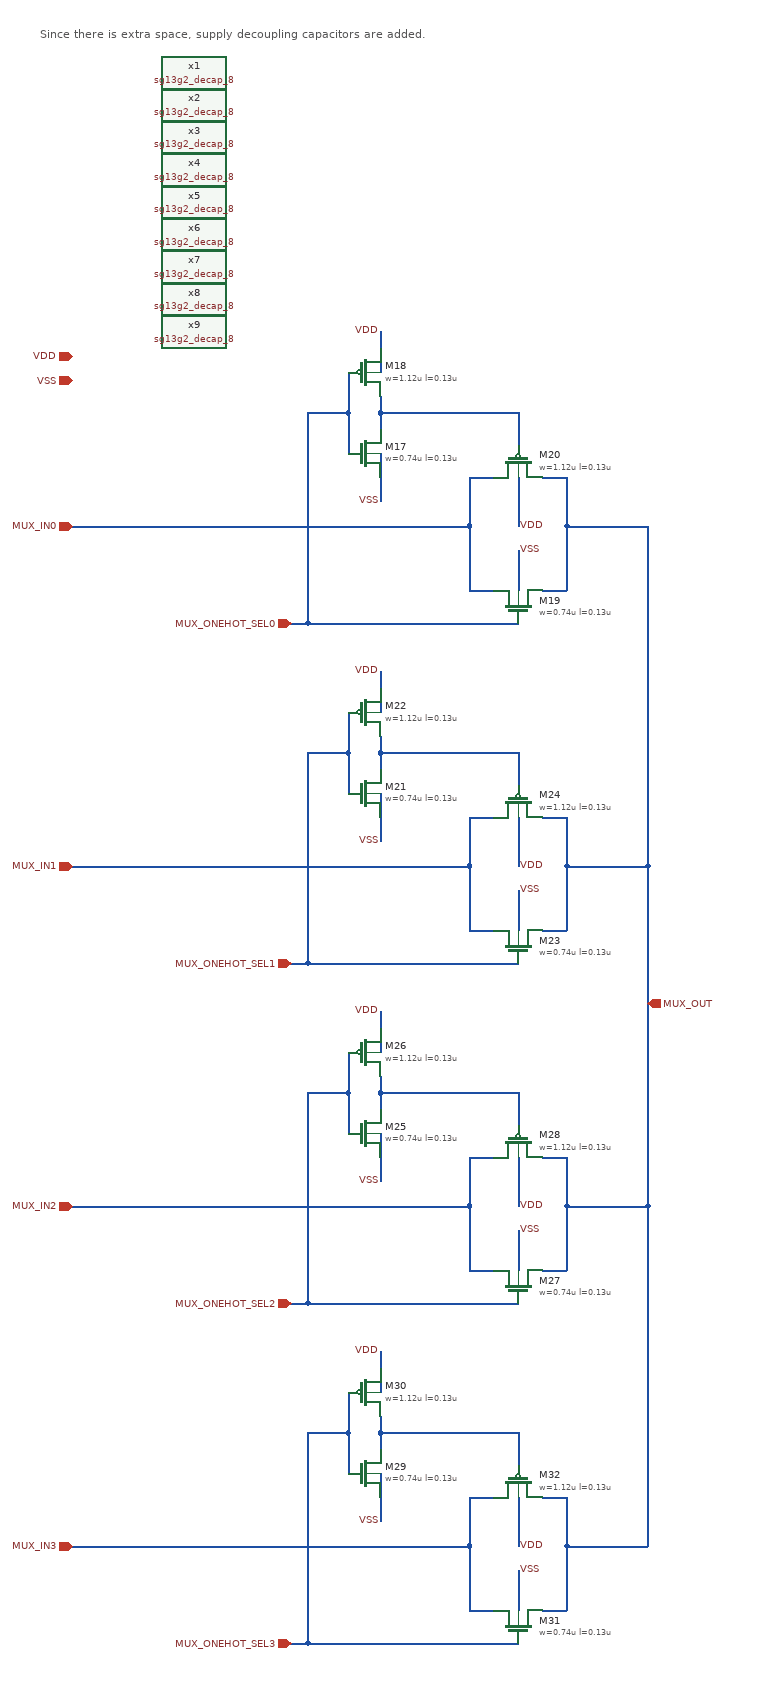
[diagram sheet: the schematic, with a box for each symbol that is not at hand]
v {xschem version=3.4.8RC file_version=1.3}
G {}
K {dash=3}
V {}
S {}
F {}
E {}
T {Since there is extra space, supply decoupling capacitors are added.} -370 -510 0 0 0.4 0.4 {}
N 50 -30 50 -10 {lab=#net1}
N 50 -30 220 -30 {lab=#net1}
N 50 -50 50 -30 {lab=#net1}
N 10 -30 10 20 {lab=MUX_ONEHOT_SEL0}
N 280 110 280 190 {lab=MUX_OUT}
N 220 50 220 110 {lab=VDD}
N 220 140 220 190 {lab=VSS}
N 280 50 280 110 {lab=MUX_OUT}
N 160 50 160 110 {lab=MUX_IN0}
N 160 50 190 50 {lab=MUX_IN0}
N 160 110 160 190 {lab=MUX_IN0}
N 160 190 190 190 {lab=MUX_IN0}
N 250 50 280 50 {lab=MUX_OUT}
N 250 190 280 190 {lab=MUX_OUT}
N 380 530 380 950 {lab=MUX_OUT}
N 220 -30 220 10 {lab=#net1}
N 10 -80 10 -30 {lab=MUX_ONEHOT_SEL0}
N -40 230 220 230 {lab=MUX_ONEHOT_SEL0}
N -40 -30 -40 230 {lab=MUX_ONEHOT_SEL0}
N -40 -30 10 -30 {lab=MUX_ONEHOT_SEL0}
N 50 -130 50 -80 {lab=VDD}
N -60 230 -40 230 {lab=MUX_ONEHOT_SEL0}
N 280 110 380 110 {lab=MUX_OUT}
N 50 20 50 80 {lab=VSS}
N 50 390 50 410 {lab=#net2}
N 50 390 220 390 {lab=#net2}
N 50 370 50 390 {lab=#net2}
N 10 390 10 440 {lab=MUX_ONEHOT_SEL1}
N 280 530 280 610 {lab=MUX_OUT}
N 220 470 220 530 {lab=VDD}
N 220 560 220 610 {lab=VSS}
N 280 470 280 530 {lab=MUX_OUT}
N 160 470 160 530 {lab=MUX_IN1}
N 160 470 190 470 {lab=MUX_IN1}
N 160 530 160 610 {lab=MUX_IN1}
N 160 610 190 610 {lab=MUX_IN1}
N 250 470 280 470 {lab=MUX_OUT}
N 250 610 280 610 {lab=MUX_OUT}
N 220 390 220 430 {lab=#net2}
N 10 340 10 390 {lab=MUX_ONEHOT_SEL1}
N -40 650 220 650 {lab=MUX_ONEHOT_SEL1}
N -40 390 -40 650 {lab=MUX_ONEHOT_SEL1}
N -40 390 10 390 {lab=MUX_ONEHOT_SEL1}
N 50 290 50 340 {lab=VDD}
N -60 650 -40 650 {lab=MUX_ONEHOT_SEL1}
N 280 530 380 530 {lab=MUX_OUT}
N 50 440 50 500 {lab=VSS}
N 380 110 380 530 {lab=MUX_OUT}
N 50 810 50 830 {lab=#net3}
N 50 810 220 810 {lab=#net3}
N 50 790 50 810 {lab=#net3}
N 10 810 10 860 {lab=MUX_ONEHOT_SEL2}
N 280 950 280 1030 {lab=MUX_OUT}
N 220 890 220 950 {lab=VDD}
N 220 980 220 1030 {lab=VSS}
N 280 890 280 950 {lab=MUX_OUT}
N 160 890 160 950 {lab=MUX_IN2}
N 160 890 190 890 {lab=MUX_IN2}
N 160 950 160 1030 {lab=MUX_IN2}
N 160 1030 190 1030 {lab=MUX_IN2}
N 250 890 280 890 {lab=MUX_OUT}
N 250 1030 280 1030 {lab=MUX_OUT}
N 220 810 220 850 {lab=#net3}
N 10 760 10 810 {lab=MUX_ONEHOT_SEL2}
N -40 1070 220 1070 {lab=MUX_ONEHOT_SEL2}
N -40 810 -40 1070 {lab=MUX_ONEHOT_SEL2}
N -40 810 10 810 {lab=MUX_ONEHOT_SEL2}
N 50 710 50 760 {lab=VDD}
N -60 1070 -40 1070 {lab=MUX_ONEHOT_SEL2}
N 50 860 50 920 {lab=VSS}
N 380 950 380 1370 {lab=MUX_OUT}
N 50 1230 50 1250 {lab=#net4}
N 50 1230 220 1230 {lab=#net4}
N 50 1210 50 1230 {lab=#net4}
N 10 1230 10 1280 {lab=MUX_ONEHOT_SEL3}
N 280 1370 280 1450 {lab=MUX_OUT}
N 220 1310 220 1370 {lab=VDD}
N 220 1400 220 1450 {lab=VSS}
N 280 1310 280 1370 {lab=MUX_OUT}
N 160 1310 190 1310 {lab=MUX_IN3}
N 160 1450 190 1450 {lab=MUX_IN3}
N 250 1310 280 1310 {lab=MUX_OUT}
N 250 1450 280 1450 {lab=MUX_OUT}
N 220 1230 220 1270 {lab=#net4}
N 10 1180 10 1230 {lab=MUX_ONEHOT_SEL3}
N -40 1490 220 1490 {lab=MUX_ONEHOT_SEL3}
N -40 1230 -40 1490 {lab=MUX_ONEHOT_SEL3}
N -40 1230 10 1230 {lab=MUX_ONEHOT_SEL3}
N 50 1130 50 1180 {lab=VDD}
N -60 1490 -40 1490 {lab=MUX_ONEHOT_SEL3}
N 280 1370 380 1370 {lab=MUX_OUT}
N 50 1280 50 1340 {lab=VSS}
N 280 950 380 950 {lab=MUX_OUT}
N 160 1370 160 1450 {lab=MUX_IN3}
N 160 1310 160 1370 {lab=MUX_IN3}
N -330 110 160 110 {lab=MUX_IN0}
N -330 530 160 530 {lab=MUX_IN1}
N -330 950 160 950 {lab=MUX_IN2}
N -330 1370 160 1370 {lab=MUX_IN3}
C {ipin.sym} -330 -100 0 0 {name=p3 lab=VDD}
C {ipin.sym} -330 -70 0 0 {name=p4 lab=VSS}
C {ipin.sym} -330 110 0 0 {name=p7 lab=MUX_IN0}
C {opin.sym} 380 700 0 0 {name=p37 lab=MUX_OUT}
C {ipin.sym} -60 230 0 0 {name=p5 lab=MUX_ONEHOT_SEL0}
C {ipin.sym} -330 530 0 0 {name=p1 lab=MUX_IN1}
C {ipin.sym} -330 950 0 0 {name=p2 lab=MUX_IN2}
C {ipin.sym} -330 1370 0 0 {name=p6 lab=MUX_IN3}
C {sg13g2_pr/sg13_lv_nmos.sym} 30 20 0 0 {name=M17
l=0.13u
w=0.74u
ng=1
m=1
model=sg13_lv_nmos
spiceprefix=X
}
C {sg13g2_pr/sg13_lv_pmos.sym} 30 -80 0 0 {name=M18
l=0.13u
w=1.12u
ng=1
m=1
model=sg13_lv_pmos
spiceprefix=X
}
C {sg13g2_pr/sg13_lv_nmos.sym} 220 210 3 0 {name=M19
l=0.13u
w=0.74u
ng=1
m=1
model=sg13_lv_nmos
spiceprefix=X
}
C {sg13g2_pr/sg13_lv_pmos.sym} 220 30 1 0 {name=M20
l=0.13u
w=1.12u
ng=1
m=1
model=sg13_lv_pmos
spiceprefix=X
}
C {lab_pin.sym} 220 110 2 0 {name=p53 lab=VDD}
C {lab_pin.sym} 220 140 2 0 {name=p17 lab=VSS}
C {lab_pin.sym} 50 -130 0 0 {name=p8 lab=VDD}
C {lab_pin.sym} 50 80 0 0 {name=p9 lab=VSS}
C {ipin.sym} -60 650 0 0 {name=p10 lab=MUX_ONEHOT_SEL1}
C {sg13g2_pr/sg13_lv_nmos.sym} 30 440 0 0 {name=M21
l=0.13u
w=0.74u
ng=1
m=1
model=sg13_lv_nmos
spiceprefix=X
}
C {sg13g2_pr/sg13_lv_pmos.sym} 30 340 0 0 {name=M22
l=0.13u
w=1.12u
ng=1
m=1
model=sg13_lv_pmos
spiceprefix=X
}
C {sg13g2_pr/sg13_lv_nmos.sym} 220 630 3 0 {name=M23
l=0.13u
w=0.74u
ng=1
m=1
model=sg13_lv_nmos
spiceprefix=X
}
C {sg13g2_pr/sg13_lv_pmos.sym} 220 450 1 0 {name=M24
l=0.13u
w=1.12u
ng=1
m=1
model=sg13_lv_pmos
spiceprefix=X
}
C {lab_pin.sym} 220 530 2 0 {name=p11 lab=VDD}
C {lab_pin.sym} 220 560 2 0 {name=p12 lab=VSS}
C {lab_pin.sym} 50 290 0 0 {name=p13 lab=VDD}
C {lab_pin.sym} 50 500 0 0 {name=p14 lab=VSS}
C {ipin.sym} -60 1070 0 0 {name=p15 lab=MUX_ONEHOT_SEL2}
C {sg13g2_pr/sg13_lv_nmos.sym} 30 860 0 0 {name=M25
l=0.13u
w=0.74u
ng=1
m=1
model=sg13_lv_nmos
spiceprefix=X
}
C {sg13g2_pr/sg13_lv_pmos.sym} 30 760 0 0 {name=M26
l=0.13u
w=1.12u
ng=1
m=1
model=sg13_lv_pmos
spiceprefix=X
}
C {sg13g2_pr/sg13_lv_nmos.sym} 220 1050 3 0 {name=M27
l=0.13u
w=0.74u
ng=1
m=1
model=sg13_lv_nmos
spiceprefix=X
}
C {sg13g2_pr/sg13_lv_pmos.sym} 220 870 1 0 {name=M28
l=0.13u
w=1.12u
ng=1
m=1
model=sg13_lv_pmos
spiceprefix=X
}
C {lab_pin.sym} 220 950 2 0 {name=p16 lab=VDD}
C {lab_pin.sym} 220 980 2 0 {name=p18 lab=VSS}
C {lab_pin.sym} 50 710 0 0 {name=p19 lab=VDD}
C {lab_pin.sym} 50 920 0 0 {name=p20 lab=VSS}
C {ipin.sym} -60 1490 0 0 {name=p21 lab=MUX_ONEHOT_SEL3}
C {sg13g2_pr/sg13_lv_nmos.sym} 30 1280 0 0 {name=M29
l=0.13u
w=0.74u
ng=1
m=1
model=sg13_lv_nmos
spiceprefix=X
}
C {sg13g2_pr/sg13_lv_pmos.sym} 30 1180 0 0 {name=M30
l=0.13u
w=1.12u
ng=1
m=1
model=sg13_lv_pmos
spiceprefix=X
}
C {sg13g2_pr/sg13_lv_nmos.sym} 220 1470 3 0 {name=M31
l=0.13u
w=0.74u
ng=1
m=1
model=sg13_lv_nmos
spiceprefix=X
}
C {sg13g2_pr/sg13_lv_pmos.sym} 220 1290 1 0 {name=M32
l=0.13u
w=1.12u
ng=1
m=1
model=sg13_lv_pmos
spiceprefix=X
}
C {lab_pin.sym} 220 1370 2 0 {name=p22 lab=VDD}
C {lab_pin.sym} 220 1400 2 0 {name=p23 lab=VSS}
C {lab_pin.sym} 50 1340 0 0 {name=p24 lab=VSS}
C {lab_pin.sym} 50 1130 0 0 {name=p25 lab=VDD}
C {sg13g2_decap_8.sym} -180 -450 0 0 {name=x1 VDD=VDD VSS=VSS prefix=sg13g2_ }
C {sg13g2_decap_8.sym} -180 -410 0 0 {name=x2 VDD=VDD VSS=VSS prefix=sg13g2_ }
C {sg13g2_decap_8.sym} -180 -370 0 0 {name=x3 VDD=VDD VSS=VSS prefix=sg13g2_ }
C {sg13g2_decap_8.sym} -180 -330 0 0 {name=x4 VDD=VDD VSS=VSS prefix=sg13g2_ }
C {sg13g2_decap_8.sym} -180 -290 0 0 {name=x5 VDD=VDD VSS=VSS prefix=sg13g2_ }
C {sg13g2_decap_8.sym} -180 -250 0 0 {name=x6 VDD=VDD VSS=VSS prefix=sg13g2_ }
C {sg13g2_decap_8.sym} -180 -210 0 0 {name=x7 VDD=VDD VSS=VSS prefix=sg13g2_ }
C {sg13g2_decap_8.sym} -180 -170 0 0 {name=x8 VDD=VDD VSS=VSS prefix=sg13g2_ }
C {sg13g2_decap_8.sym} -180 -130 0 0 {name=x9 VDD=VDD VSS=VSS prefix=sg13g2_ }
